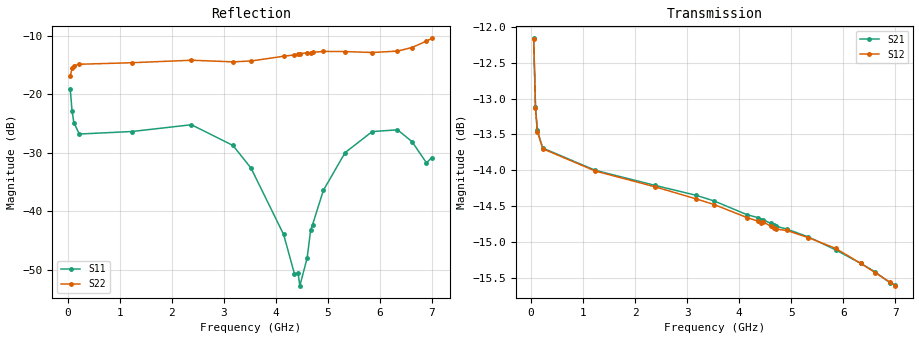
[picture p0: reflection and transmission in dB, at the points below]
! Integrated Device Technology
! Corporate Headquarters
! 6024 Silver Creek Valley Road
! San Jose, CA 95138  USA
! Phone:  1-408-284-8200
! Toll Free:  1-800-223-1366
! Webpage:  http://www.idt.com/
! Timing and RF Division
! 515 Groton Road, Suite 102
! Westford, MA 01886-6024
! Device:  F2258
! Description: Voltage Variable RF Attenuator
! Frequency:  50.0 -  6000.00 MHz
! Package:  3x3 mm Thin QFN Plastic Package: 16 pin
! Ports:  2 RF, 2 DC
!  Pin  1  = NC
!  Pin  2  = NC
!  Pin  3  = RF2  = Port 2
!  Pin  4  = GND
!  Pin  5  = Vdd
!  Pin  6  = NC
!  Pin  7  = VCTRL
!  Pin  8  = NC
!  Pin  9  = GND
!  Pin 10  = RF1  = Port 1
!  Pin 11  = NC
!  Pin 12  = NC
!  Pin 13  = NC
!  Pin 14  = NC
!  Pin 15  = NC
!  Pin 16  = NC
! Vcntrl:  1.140 Volts
! Vdd:  +3.300 Volts
! Current:  1.162 mA
! Data:  The device was measured on a the F2258 evaluation board which has
!  individual transmission lines to the RF pins.  Data was collected
!  using a calibrated network analyzer.  The evaluation board was
!  de-embedded using a TRL calibration technique.
!  The reference plane is the edge of the package pin.
! Misc:  SN 10
!  Action Tracker AT0285
! Date Measured:  2014-12-10
! Date:  2016-01-13  MJV
! Note:
!  Integrated Device Technology supplies this data as a sample of measured
!  data at the package pin for this product.  Your particular data for this
!  product may vary.
!  Data was taken at 25 degrees C.
!  Integrated Device Technology reserves the right to change this data at anytime.
!Freq_(GHz)  S11M_(dB)  S11P_(deg)  S21M_(dB)  S21P_(deg)  S12M_(dB)  S12P_(deg)  S22M_(dB)  S22P_(deg)
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# GHz S dB R 50
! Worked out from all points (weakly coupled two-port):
!   201 points, 50 MHz to 7 GHz, reference 50 ohm
!   highest |S21| = -12.16 dB at 50 MHz (marker M1); lowest = -15.6 dB at 7 GHz (marker M2)
!   lowest |S11| = -52.8 dB at 4.463 GHz (marker M3), VSWR 1.00, Z = 50.2 - j0.00349 ohm
!   |S11| at or under -10 dB: start of sweep to end of sweep
!   |S22| runs from -16.9 to -10.4 dB; largest |S21 - S12| = 0.0016
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0.05  -19.13 -88.8  -12.16 -21.2  -12.17 -21.2  -16.86 -24.0
0.08475  -22.91 -70.1  -13.12 -15.2  -13.13 -15.2  -15.55 -13.3
0.1195  -24.87 -56.1  -13.44 -12.2  -13.46 -12.2  -15.15 -10.8
0.22375  -26.81 -34.1  -13.69 -9.5  -13.70 -9.5  -14.87 -10.1
1.2315  -26.38 -16.5  -14.00 -20.9  -14.01 -20.9  -14.61 -36.0
2.37825  -25.22 -6.3  -14.21 -37.9  -14.23 -37.9  -14.18 -64.2
3.1775  -28.77 4.5  -14.35 -50.1  -14.40 -50.0  -14.46 -89.2
3.525  -32.65 12.6  -14.43 -55.4  -14.48 -55.4  -14.31 -102.9
4.1505  -43.99 44.1  -14.62 -64.9  -14.66 -64.9  -13.50 -123.8
4.359  -50.72 19.9  -14.66 -68.1  -14.71 -68.1  -13.27 -129.7
4.4285  -50.62 6.2  -14.69 -69.2  -14.74 -69.1  -13.15 -131.1
4.46325  -52.76 -0.9  -14.69 -69.7  -14.72 -69.6  -13.10 -132.3
4.60225  -48.06 -29.8  -14.74 -71.6  -14.78 -71.6  -12.88 -134.6
4.67175  -43.18 -34.2  -14.77 -72.7  -14.81 -72.6  -12.87 -135.5
4.7065  -42.34 -36.4  -14.78 -73.2  -14.82 -73.1  -12.84 -136.3
4.915  -36.45 -38.8  -14.82 -76.3  -14.84 -76.3  -12.67 -139.6
5.332  -30.00 -28.8  -14.93 -82.3  -14.94 -82.2  -12.70 -145.6
5.85325  -26.39 -15.7  -15.11 -89.7  -15.09 -89.7  -12.86 -155.2
6.33975  -26.09 -0.6  -15.30 -96.7  -15.30 -96.7  -12.62 -167.3
6.61775  -28.09 19.9  -15.42 -100.4  -15.43 -100.5  -12.01 -175.2
6.89575  -31.73 67.9  -15.57 -104.1  -15.56 -104.1  -10.91 177.3
7  -30.85 96.6  -15.60 -105.4  -15.61 -105.4  -10.44 174.8
